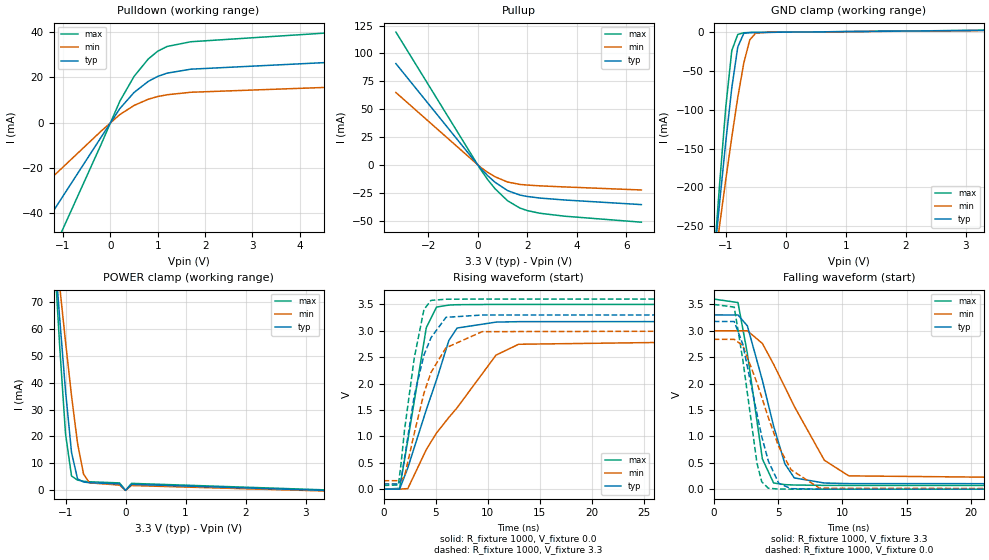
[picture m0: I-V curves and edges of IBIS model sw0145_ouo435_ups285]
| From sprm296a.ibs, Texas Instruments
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[Model]   sw0145_ouo435_ups285
Model_type   I/O
| I/O with PULLUP
Vinh = 2.00
Vinl = 0.80
Enable   Active-Low
Polarity   Non-Inverting
| signals   A, GZ, Y
Vmeas = 1.5
|   typ   min   max
C_comp   4.540p   4.446p   5.074p
|   typ   min   max
[Temperature Range]   25   -40   125
|   typ   min   max
[Voltage Range]   3.30V   3.00V   3.60V
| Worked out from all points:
|   slope of the pulldown table from 0 to 0.495 V, typ, clamps not added: 37.7 ohm
|   slope of the pullup table from 0 to 0.495 V, typ, clamps not added: 42.7 ohm
|   GND clamp passes 1 mA (typ) near -0.65 V on its own axis
|   POWER clamp passes 1 mA (typ) near -0.04 V on its own axis
|   rising waveform, R_fixture 1000, V_fixture 0.0: 20-80 % time 3.17ns typ, 6.14ns min, 1.77ns max; typ from 0 V to 3.18 V
|   falling waveform, R_fixture 1000, V_fixture 3.3: 20-80 % time 2.02ns typ, 3.58ns min, 1.23ns max; typ from 3.3 V to 0.099 V
|   rising waveform, R_fixture 1000, V_fixture 3.3: 20-80 % time 1.97ns typ, 2.5ns min, 1.5ns max; typ from 0.099 V to 3.3 V
|   falling waveform, R_fixture 1000, V_fixture 0.0: 20-80 % time 1.66ns typ, 2.52ns min, 1.14ns max; typ from 3.18 V to 0 V
[Pulldown]
|   Voltage   I(typ)   I(min)   I(max)
-3.3V     -106.6mA   -64.96mA   -153.1mA
-200mV    -6.638mA   -3.888mA   -9.861mA
200mV     6.136mA    3.487mA    9.379mA
500mV     13.23mA    7.514mA    20.3mA
800mV     18.12mA    10.25mA    27.98mA
1V        20.32mA    11.45mA    31.43mA
1.2V      21.76mA    12.24mA    33.52mA
1.7V      23.5mA     13.33mA    35.59mA
6.6V      28.52mA    17mA       42.18mA
[GND_clamp]
|   Voltage   I(typ)   I(min)   I(max)
-3.3V     -2.102A    -1.61A     -2.692A
-1.2V     -297.1mA   -305.5mA   -297.4mA
-1.1V     -217.5mA   -247.2mA   -193mA
-1V       -141.3mA   -190.2mA   -96.75mA
-900mV    -71.93mA   -135.4mA   -23.73mA
-800mV    -19.11mA   -84.21mA   -2.975mA
-700mV    -1.614mA   -39.84mA   -770uA
-600mV    -491.7uA   -9.928mA   -479.7uA
-500mV    -375.2uA   -1.161mA   -389.5uA
-300mV    -223.6uA   -207.1uA   -233.3uA
3.3V      2.314mA    2.102mA    2.437mA
[Pullup]
|   Voltage   I(typ)   I(min)   I(max)
-3.3V     90.83mA    64.92mA    119.1mA
100mV     -2.569mA   -1.78mA    -3.482mA
400mV     -9.588mA   -6.59mA    -13.07mA
700mV     -15.54mA   -10.57mA   -21.33mA
1.2V      -22.92mA   -15.27mA   -32mA
1.7V      -26.98mA   -17.44mA   -38.62mA
2V        -28.23mA   -18.01mA   -40.89mA
2.5V      -29.63mA   -18.7mA    -43.25mA
3.5V      -31.38mA   -19.68mA   -45.9mA
6.6V      -35.51mA   -22.41mA   -51.28mA
[POWER_clamp]
|   Voltage   I(typ)   I(min)   I(max)
-3.3V     778.2mA    598.5mA    994.4mA
-1.2V     94.13mA    98.35mA    92.75mA
-1.1V     64.61mA    76.41mA    54.44mA
-1V       36.92mA    55.15mA    20.99mA
-900mV    14.06mA    35.1mA     5.343mA
-800mV    4.28mA     17.55mA    3.813mA
-700mV    3.096mA    6.044mA    3.355mA
-600mV    2.832mA    2.793mA    3.184mA
-100mV    2.395mA    1.951mA    2.761mA
0V        1pA        1pA        1pA
100mV     2.231mA    1.791mA    2.594mA
3.3V      -23.23uA   -221.2uA   195.4uA
[Ramp]
|   I(typ)   I(min)   I(max)
dV/dt_r   1.905/3.173n   1.703/6.138n   2.100/1.774n
dV/dt_f   1.920/2.018n   1.704/3.578n   2.118/1.226n
[Rising Waveform]
R_fixture = 1000
V_fixture = 0.0
|  pu_on
|  TIME   V(typ)   V(min)   V(max)
0s        7nV        18nV       5nV
1.533ns   420.4uV    516.3uV    14.94mV
2.322ns   404.9mV    11.07mV    921.2mV
4.097ns   1.503V     750.1mV    3.059V
5.083ns   2.072V     1.065V     3.449V
6.266ns   2.815V     1.359V     3.486V
7.054ns   3.051V     1.541V     3.493V
10.8ns    3.164V     2.539V     3.499V
12.97ns   3.172V     2.744V     3.499V
50ns      3.176V     2.838V     3.499V
[Falling Waveform]
R_fixture = 1000
V_fixture = 3.3
V_fixture_min = 3.0
V_fixture_max = 3.6
|  pd_on
|  TIME   V(typ)   V(min)   V(max)
0s        3.3V       3V         3.6V
1.881ns   3.299V     2.999V     3.534V
2.611ns   3.093V     2.999V     2.572V
3.779ns   2.062V     2.76V      572.7mV
4.655ns   1.194V     2.364V     116.9mV
5.532ns   479.3mV    1.933V     85.8mV
6.262ns   213.2mV    1.569V     78.74mV
8.598ns   116.2mV    548.5mV    72.09mV
10.5ns    105.6mV    251.8mV    71.08mV
50ns      99.39mV    159.8mV    70.79mV
[Rising Waveform]
R_fixture = 1000
V_fixture = 3.3
V_fixture_min = 3.0
V_fixture_max = 3.6
|  pd_off
|  TIME   V(typ)   V(min)   V(max)
0s        99.39mV    159.8mV    70.79mV
1.415ns   99.39mV    160.3mV    78.71mV
1.67ns    172.2mV    160.3mV    481.9mV
2.008ns   587.8mV    245.2mV    1.123V
2.94ns    1.77V      1.056V     2.483V
3.872ns   2.54V      1.819V     3.402V
4.55ns    2.869V     2.211V     3.575V
5.99ns    3.254V     2.678V     3.597V
9.464ns   3.298V     2.983V     3.6V
50ns      3.3V       3V         3.6V
[Falling Waveform]
R_fixture = 1000
V_fixture = 0.0
|  pu_off
|  TIME   V(typ)   V(min)   V(max)
0s        3.176V     2.838V     3.499V
1.592ns   3.175V     2.837V     3.448V
2.255ns   2.746V     2.721V     2.457V
3.361ns   1.427V     2.013V     490.4mV
3.73ns    997.4mV    1.741V     140.1mV
4.246ns   530.7mV    1.353V     17.22mV
5.057ns   110.7mV    802.1mV    2.131mV
6.015ns   9.353mV    366.2mV    643.1uV
8.227ns   629.9uV    18.55mV    108uV
50ns      982.4nV    1.519uV    384.9nV
